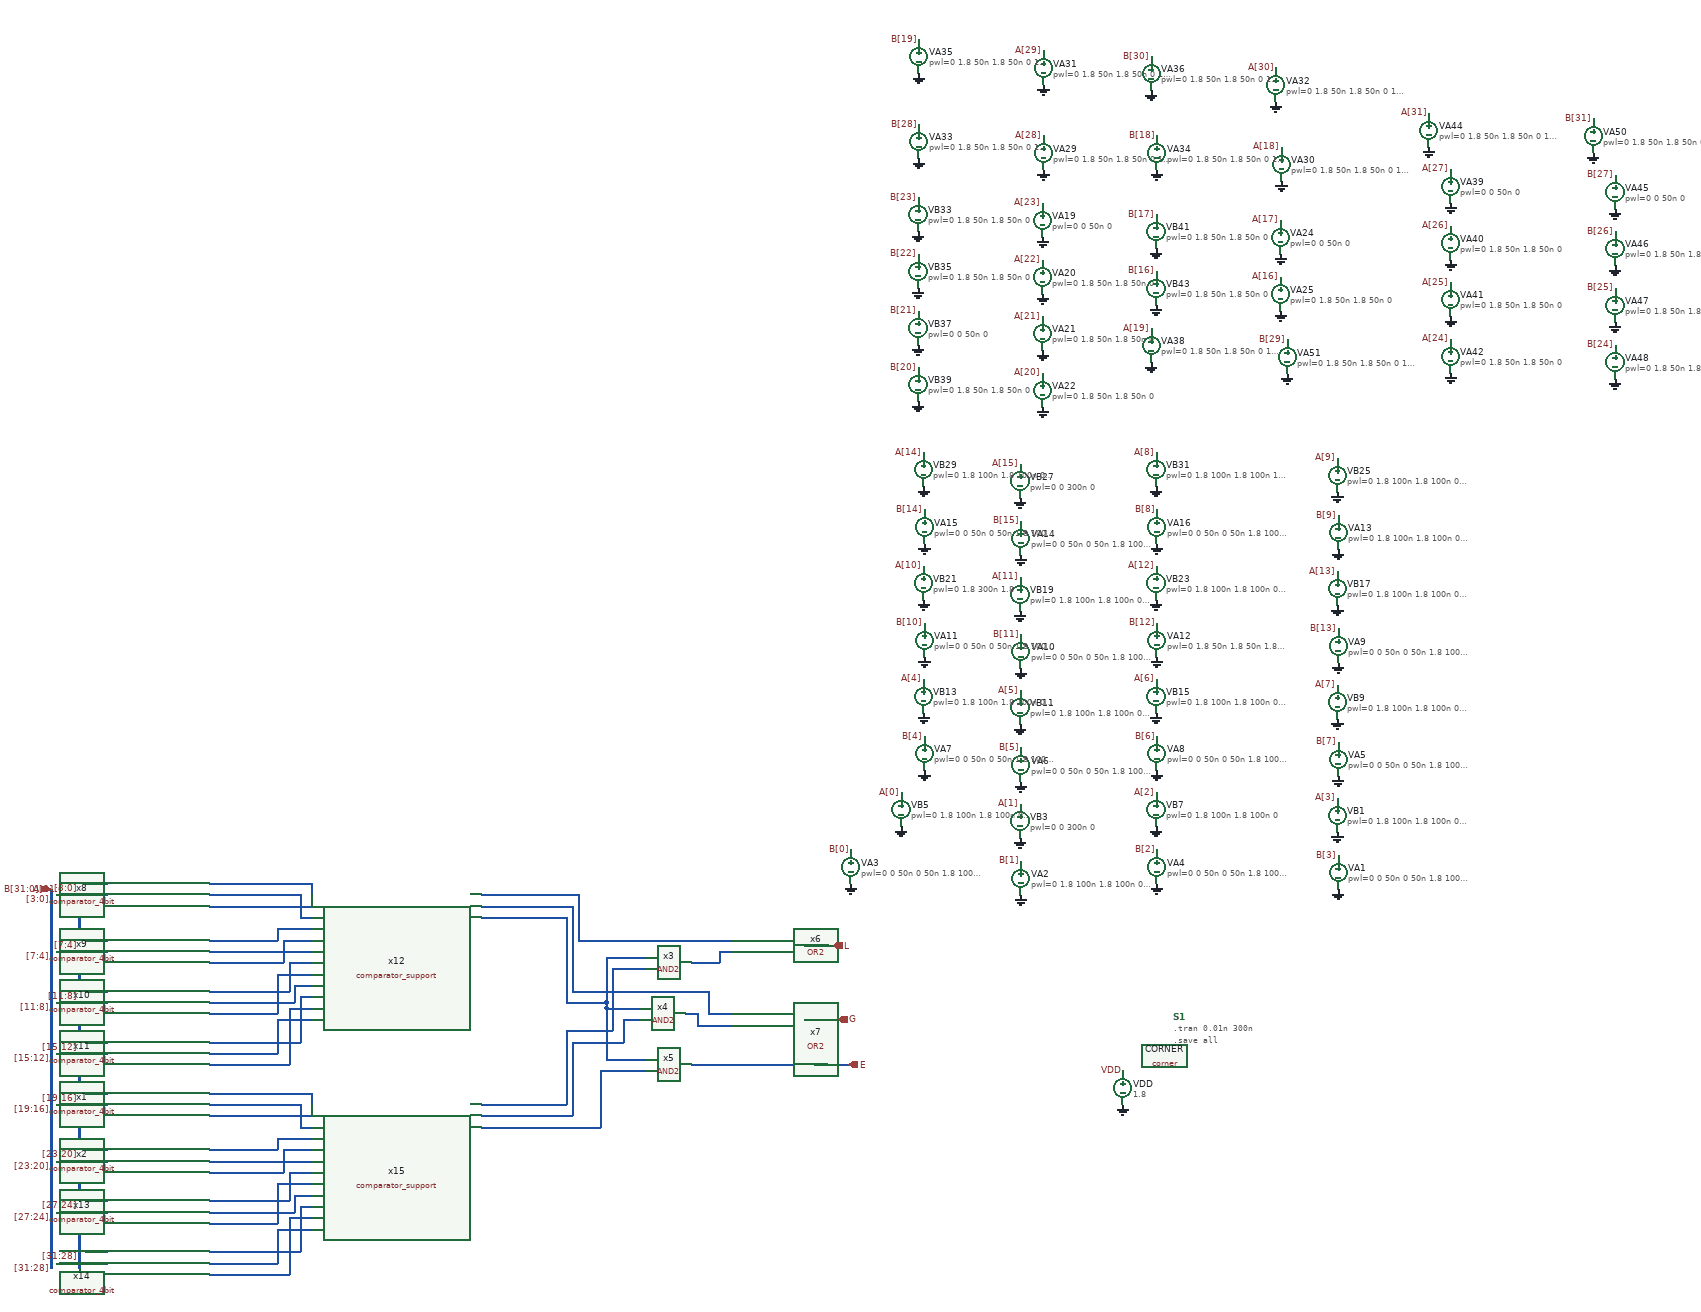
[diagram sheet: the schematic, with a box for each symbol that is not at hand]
v {xschem version=3.4.5 file_version=1.2
}
G {}
K {}
V {}
S {}
E {}
B 2 1100 -540 1900 -140 {flags=graph
y1=0
y2=2
ypos1=-0.3
ypos2=1.7
divy=5
subdivy=1
unity=1
x1=3e-08
x2=1.3e-07
divx=5
subdivx=1
xlabmag=1.0
ylabmag=1.0


dataset=-1
unitx=1
logx=0
logy=0
digital=1
color="12 12 10 10 10"
node="A;a[31],a[30],a[29],a[28],a[27],a[26],a[25],a[24],a[23],a[22],a[21],a[20],a[19],a[18],a[17],a[16],a[15],a[14],a[13],a[12],a[11],a[10],a[9],a[8],a[7],a[6],a[5],a[4],a[3],a[2],a[1],a[0]
B;b[31],b[30],b[29],b[28],b[27],b[26],b[25],b[24],b[23],b[22],b[21],b[20],b[19],b[18],b[17],b[16],b[15],b[14],b[13],b[12],b[11],b[10],b[9],b[8],b[7],b[6],b[5],b[4],b[3],b[2],b[1],b[0]
g
e
l"}
N 550 -960 820 -960 {
lab=#net1}
N 550 -850 570 -850 {
lab=#net2}
N 570 -850 600 -850 {
lab=#net2}
N 600 -930 600 -850 {
lab=#net2}
N 600 -930 670 -930 {
lab=#net2}
N 550 -800 610 -800 {
lab=#net3}
N 610 -910 610 -800 {
lab=#net3}
N 610 -910 670 -910 {
lab=#net3}
N 750 -920 800 -920 {
lab=#net4}
N 800 -940 800 -920 {
lab=#net4}
N 800 -940 820 -940 {
lab=#net4}
N 550 -870 780 -870 {
lab=#net5}
N 780 -870 780 -830 {
lab=#net5}
N 780 -830 820 -830 {
lab=#net5}
N 600 -850 600 -840 {
lab=#net2}
N 600 -840 660 -840 {
lab=#net2}
N 550 -780 630 -780 {
lab=#net6}
N 630 -820 630 -780 {
lab=#net6}
N 630 -820 660 -820 {
lab=#net6}
N 740 -830 760 -830 {
lab=#net7}
N 760 -830 760 -810 {
lab=#net7}
N 760 -810 820 -810 {
lab=#net7}
N 600 -840 600 -750 {
lab=#net2}
N 600 -750 670 -750 {
lab=#net2}
N 590 -730 670 -730 {
lab=#net8}
N 750 -740 990 -740 {
lab=E}
N 949 -820 1009 -820 {
lab=G}
N 968 -740 1028 -740 {
lab=E}
N 991 -950 1001 -950 {
lab=L}
N 949 -950 992 -950 {
lab=L}
N -100 -1020 0 -1020 {
lab=#net9}
N -100 -920 0 -920 {
lab=#net10}
N -100 -830 0 -830 {
lab=#net11}
N -100 -740 0 -740 {
lab=#net12}
N -100 -1060 -20 -1060 {
lab=#net13}
N -100 -960 -60 -960 {
lab=#net14}
N -100 -870 -20 -870 {
lab=#net15}
N -100 -780 -20 -780 {
lab=#net16}
N -100 -760 -40 -760 {
lab=#net17}
N -100 -1040 -40 -1040 {
lab=#net18}
N -100 -940 -40 -940 {
lab=#net19}
N -100 -850 -40 -850 {
lab=#net20}
N 80 -1060 80 -1040 {
lab=#net13}
N -20 -1060 80 -1060 {
lab=#net13}
N 0 -1020 80 -1020 {
lab=#net9}
N -40 -1040 60 -1040 {
lab=#net18}
N 60 -1040 60 -1000 {
lab=#net18}
N 60 -1000 80 -1000 {
lab=#net18}
N -60 -960 20 -960 {
lab=#net14}
N 20 -980 20 -960 {
lab=#net14}
N 20 -980 80 -980 {
lab=#net14}
N -40 -940 80 -940 {
lab=#net19}
N 70 -960 80 -960 {
lab=#net10}
N -20 -870 30 -870 {
lab=#net15}
N 0 -920 30 -920 {
lab=#net10}
N 30 -960 30 -920 {
lab=#net10}
N 30 -960 70 -960 {
lab=#net10}
N 30 -870 40 -870 {
lab=#net15}
N 40 -920 40 -870 {
lab=#net15}
N 40 -920 80 -920 {
lab=#net15}
N -40 -850 50 -850 {
lab=#net20}
N 50 -880 50 -850 {
lab=#net20}
N 50 -880 80 -880 {
lab=#net20}
N 0 -830 20 -830 {
lab=#net11}
N 20 -900 20 -830 {
lab=#net11}
N 20 -900 80 -900 {
lab=#net11}
N -20 -780 60 -780 {
lab=#net16}
N 60 -860 60 -780 {
lab=#net16}
N 60 -860 80 -860 {
lab=#net16}
N 40 -840 80 -840 {
lab=#net12}
N 40 -840 40 -740 {
lab=#net12}
N 0 -740 40 -740 {
lab=#net12}
N -40 -760 20 -760 {
lab=#net17}
N 20 -820 20 -760 {
lab=#net17}
N 20 -820 80 -820 {
lab=#net17}
N -100 -650 0 -650 {
lab=#net21}
N -100 -550 0 -550 {
lab=#net22}
N -100 -460 0 -460 {
lab=#net23}
N -100 -370 0 -370 {
lab=#net24}
N -100 -690 -20 -690 {
lab=#net25}
N -100 -590 -60 -590 {
lab=#net26}
N -100 -500 -20 -500 {
lab=#net27}
N -100 -410 -20 -410 {
lab=#net28}
N -100 -390 -40 -390 {
lab=#net29}
N -100 -670 -40 -670 {
lab=#net30}
N -100 -570 -40 -570 {
lab=#net31}
N -100 -480 -40 -480 {
lab=#net32}
N 80 -690 80 -670 {
lab=#net25}
N -20 -690 80 -690 {
lab=#net25}
N 0 -650 80 -650 {
lab=#net21}
N -40 -670 60 -670 {
lab=#net30}
N 60 -670 60 -630 {
lab=#net30}
N 60 -630 80 -630 {
lab=#net30}
N -60 -590 20 -590 {
lab=#net26}
N 20 -610 20 -590 {
lab=#net26}
N 20 -610 80 -610 {
lab=#net26}
N -40 -570 80 -570 {
lab=#net31}
N 70 -590 80 -590 {
lab=#net22}
N -20 -500 30 -500 {
lab=#net27}
N 0 -550 30 -550 {
lab=#net22}
N 30 -590 30 -550 {
lab=#net22}
N 30 -590 70 -590 {
lab=#net22}
N 30 -500 40 -500 {
lab=#net27}
N 40 -550 40 -500 {
lab=#net27}
N 40 -550 80 -550 {
lab=#net27}
N -40 -480 50 -480 {
lab=#net32}
N 50 -510 50 -480 {
lab=#net32}
N 50 -510 80 -510 {
lab=#net32}
N 0 -460 20 -460 {
lab=#net23}
N 20 -530 20 -460 {
lab=#net23}
N 20 -530 80 -530 {
lab=#net23}
N -20 -410 60 -410 {
lab=#net28}
N 60 -490 60 -410 {
lab=#net28}
N 60 -490 80 -490 {
lab=#net28}
N 40 -470 80 -470 {
lab=#net24}
N 40 -470 40 -370 {
lab=#net24}
N 0 -370 40 -370 {
lab=#net24}
N -40 -390 20 -390 {
lab=#net29}
N 20 -450 20 -390 {
lab=#net29}
N 20 -450 80 -450 {
lab=#net29}
N 380 -1040 550 -1040 {
lab=#net1}
N 550 -1040 550 -960 {
lab=#net1}
N 380 -1000 530 -1000 {
lab=#net2}
N 530 -1000 530 -850 {
lab=#net2}
N 530 -850 550 -850 {
lab=#net2}
N 380 -670 530 -670 {
lab=#net3}
N 530 -800 530 -670 {
lab=#net3}
N 530 -800 550 -800 {
lab=#net3}
N 380 -1020 540 -1020 {
lab=#net5}
N 540 -1020 540 -870 {
lab=#net5}
N 540 -870 550 -870 {
lab=#net5}
N 380 -650 540 -650 {
lab=#net6}
N 540 -780 540 -650 {
lab=#net6}
N 540 -780 550 -780 {
lab=#net6}
N 380 -630 590 -630 {
lab=#net8}
N 590 -730 590 -630 {
lab=#net8}
N -330 -1050 -330 -430 {bus=true lab=A[31:0]}
N -380 -1050 -380 -430 {bus=true lab=B[31:0]}
N -370 -760 -280 -760 {
lab=B[15:12]}
N -320 -780 -280 -780 {
lab=A[15:12]}
N -370 -850 -280 -850 {
lab=B[11:8]}
N -320 -870 -280 -870 {
lab=A[11:8]}
N -370 -940 -280 -940 {
lab=B[7:4]}
N -320 -960 -280 -960 {
lab=A[7:4]}
N -370 -1040 -280 -1040 {
lab=B[3:0]}
N -320 -1060 -280 -1060 {
lab=A[3:0]}
N -380 -430 -380 -380 {
bus=true lab=B[31:0]}
N -330 -430 -330 -380 {bus=true lab=A[31:0]}
N -370 -390 -280 -390 {
lab=B[31:28]}
N -320 -410 -280 -410 {
lab=A[31:28]}
N -370 -480 -280 -480 {
lab=B[27:24]}
N -320 -500 -280 -500 {
lab=A[27:24]}
N -370 -570 -280 -570 {
lab=B[23:20]}
N -320 -590 -280 -590 {
lab=A[23:20]}
N -370 -670 -280 -670 {
lab=B[19:16]}
N -320 -690 -280 -690 {
lab=A[19:16]}
C {devices/ipin.sym} -330 -1050 1 0 {name=p16 sig_type=std_logic lab=A[31:0]}
C {devices/ipin.sym} -380 -1050 1 0 {name=p17 sig_type=std_logic lab=B[31:0]}
C {AND2.sym} 710 -920 0 0 {name=x3}
C {AND2.sym} 700 -830 0 0 {name=x4}
C {AND2.sym} 710 -740 0 0 {name=x5}
C {OR2.sym} 870 -950 0 0 {name=x6}
C {OR2.sym} 870 -820 0 0 {name=x7}
C {devices/opin.sym} 1001 -950 0 0 {name=p8 sig_type=std_logic lab=L}
C {devices/opin.sym} 1009 -820 0 0 {name=p1 sig_type=std_logic lab=G}
C {devices/opin.sym} 1028 -740 0 0 {name=p2 sig_type=std_logic lab=E}
C {devices/vsource.sym} 1511.46728515625 -698.88671875 0 0 {name=VDD value=1.8 savecurrent=false}
C {devices/lab_pin.sym} 1511.46728515625 -728.88671875 0 0 {name=VDD1 sig_type=std_logic lab=VDD}
C {devices/gnd.sym} 1511.46728515625 -668.88671875 0 0 {name=VDD2 lab=GND}
C {devices/vsource.sym} 1891.46728515625 -1078.88671875 0 0 {name=VA1 value="pwl=0 0 50n 0 50n 1.8 100n 1.8 100n 0 300n 0" savecurrent=false}
C {devices/lab_pin.sym} 1891.46728515625 -1108.88671875 0 0 {name=p3 sig_type=std_logic lab=B[3]}
C {devices/gnd.sym} 1891.46728515625 -1048.88671875 0 0 {name=l9 lab=GND}
C {devices/vsource.sym} 1890 -1180 0 0 {name=VB1 value="pwl=0 1.8 100n 1.8 100n 0 300n 0" savecurrent=false}
C {devices/lab_pin.sym} 1890 -1210 0 0 {name=VB2 sig_type=std_logic lab=A[3]}
C {devices/gnd.sym} 1890 -1150 0 0 {name=l10 lab=GND}
C {devices/code_shown.sym} 1600 -825 0 0 {name=S1 only_toplevel=false value=".tran 0.01n 300n
.save all"}
C {sky130_fd_pr/corner.sym} 1585 -755 0 0 {name=CORNER only_toplevel=true corner=tt}
C {devices/vsource.sym} 1331.46728515625 -1068.88671875 0 0 {name=VA2 value="pwl=0 1.8 100n 1.8 100n 0 300n 0" savecurrent=false}
C {devices/lab_pin.sym} 1331.46728515625 -1098.88671875 0 0 {name=p6 sig_type=std_logic lab=B[1]}
C {devices/gnd.sym} 1331.46728515625 -1038.88671875 0 0 {name=l11 lab=GND}
C {devices/vsource.sym} 1330 -1170 0 0 {name=VB3 value="pwl=0 0 300n 0" savecurrent=false}
C {devices/lab_pin.sym} 1330 -1200 0 0 {name=VB4 sig_type=std_logic lab=A[1]}
C {devices/gnd.sym} 1330 -1140 0 0 {name=l12 lab=GND}
C {devices/vsource.sym} 1031.46728515625 -1088.88671875 0 0 {name=VA3 value="pwl=0 0 50n 0 50n 1.8 100n 1.8 100n 0 300n 0" savecurrent=false}
C {devices/lab_pin.sym} 1031.46728515625 -1118.88671875 0 0 {name=p7 sig_type=std_logic lab=B[0]}
C {devices/gnd.sym} 1031.46728515625 -1058.88671875 0 0 {name=l13 lab=GND}
C {devices/vsource.sym} 1120 -1190 0 0 {name=VB5 value="pwl=0 1.8 100n 1.8 100n 0 300n 0" savecurrent=false}
C {devices/lab_pin.sym} 1120 -1220 0 0 {name=VB6 sig_type=std_logic lab=A[0]}
C {devices/gnd.sym} 1120 -1160 0 0 {name=l14 lab=GND}
C {devices/vsource.sym} 1571.46728515625 -1088.88671875 0 0 {name=VA4 value="pwl=0 0 50n 0 50n 1.8 100n 1.8 100n 0 300n 0" savecurrent=false}
C {devices/lab_pin.sym} 1571.46728515625 -1118.88671875 0 0 {name=p9 sig_type=std_logic lab=B[2]}
C {devices/gnd.sym} 1571.46728515625 -1058.88671875 0 0 {name=l15 lab=GND}
C {devices/vsource.sym} 1570 -1190 0 0 {name=VB7 value="pwl=0 1.8 100n 1.8 100n 0" savecurrent=false}
C {devices/lab_pin.sym} 1570 -1220 0 0 {name=VB8 sig_type=std_logic lab=A[2]}
C {devices/gnd.sym} 1570 -1160 0 0 {name=l16 lab=GND}
C {devices/vsource.sym} 1891.46728515625 -1278.88671875 0 0 {name=VA5 value="pwl=0 0 50n 0 50n 1.8 100n 1.8 100n 0 300n 0" savecurrent=false}
C {devices/lab_pin.sym} 1891.46728515625 -1308.88671875 0 0 {name=p4 sig_type=std_logic lab=B[7]}
C {devices/gnd.sym} 1891.46728515625 -1248.88671875 0 0 {name=l17 lab=GND}
C {devices/vsource.sym} 1890 -1380 0 0 {name=VB9 value="pwl=0 1.8 100n 1.8 100n 0 300n 0" savecurrent=false}
C {devices/lab_pin.sym} 1890 -1410 0 0 {name=VB10 sig_type=std_logic lab=A[7]}
C {devices/gnd.sym} 1890 -1350 0 0 {name=l18 lab=GND}
C {devices/vsource.sym} 1331.46728515625 -1268.88671875 0 0 {name=VA6 value="pwl=0 0 50n 0 50n 1.8 100n 1.8 100n 0 300n 0" savecurrent=false}
C {devices/lab_pin.sym} 1331.46728515625 -1298.88671875 0 0 {name=p5 sig_type=std_logic lab=B[5]}
C {devices/gnd.sym} 1331.46728515625 -1238.88671875 0 0 {name=l19 lab=GND}
C {devices/vsource.sym} 1330 -1370 0 0 {name=VB11 value="pwl=0 1.8 100n 1.8 100n 0 300n 0" savecurrent=false}
C {devices/lab_pin.sym} 1330 -1400 0 0 {name=VB12 sig_type=std_logic lab=A[5]}
C {devices/gnd.sym} 1330 -1340 0 0 {name=l20 lab=GND}
C {devices/vsource.sym} 1161.46728515625 -1288.88671875 0 0 {name=VA7 value="pwl=0 0 50n 0 50n 1.8 100n 1.8 100n 0 300n 0" savecurrent=false}
C {devices/lab_pin.sym} 1161.46728515625 -1318.88671875 0 0 {name=p10 sig_type=std_logic lab=B[4]}
C {devices/gnd.sym} 1161.46728515625 -1258.88671875 0 0 {name=l21 lab=GND}
C {devices/vsource.sym} 1160 -1390 0 0 {name=VB13 value="pwl=0 1.8 100n 1.8 100n 0 300n 0" savecurrent=false}
C {devices/lab_pin.sym} 1160 -1420 0 0 {name=VB14 sig_type=std_logic lab=A[4]}
C {devices/gnd.sym} 1160 -1360 0 0 {name=l22 lab=GND}
C {devices/vsource.sym} 1571.46728515625 -1288.88671875 0 0 {name=VA8 value="pwl=0 0 50n 0 50n 1.8 100n 1.8 100n 0 300n 0" savecurrent=false}
C {devices/lab_pin.sym} 1571.46728515625 -1318.88671875 0 0 {name=p11 sig_type=std_logic lab=B[6]}
C {devices/gnd.sym} 1571.46728515625 -1258.88671875 0 0 {name=l23 lab=GND}
C {devices/vsource.sym} 1570 -1390 0 0 {name=VB15 value="pwl=0 1.8 100n 1.8 100n 0 300n 0" savecurrent=false}
C {devices/lab_pin.sym} 1570 -1420 0 0 {name=VB16 sig_type=std_logic lab=A[6]}
C {devices/gnd.sym} 1570 -1360 0 0 {name=l24 lab=GND}
C {devices/vsource.sym} 1891.46728515625 -1478.88671875 0 0 {name=VA9 value="pwl=0 0 50n 0 50n 1.8 100n 1.8 100n 0 300n 0" savecurrent=false}
C {devices/lab_pin.sym} 1891.46728515625 -1508.88671875 0 0 {name=p12 sig_type=std_logic lab=B[13]}
C {devices/gnd.sym} 1891.46728515625 -1448.88671875 0 0 {name=l25 lab=GND}
C {devices/vsource.sym} 1890 -1580 0 0 {name=VB17 value="pwl=0 1.8 100n 1.8 100n 0 300n 0" savecurrent=false}
C {devices/lab_pin.sym} 1890 -1610 0 0 {name=VB18 sig_type=std_logic lab=A[13]}
C {devices/gnd.sym} 1890 -1550 0 0 {name=l26 lab=GND}
C {devices/vsource.sym} 1331.46728515625 -1468.88671875 0 0 {name=VA10 value="pwl=0 0 50n 0 50n 1.8 100n 1.8 100n 0 300n 0" savecurrent=false}
C {devices/lab_pin.sym} 1331.46728515625 -1498.88671875 0 0 {name=p13 sig_type=std_logic lab=B[11]}
C {devices/gnd.sym} 1331.46728515625 -1438.88671875 0 0 {name=l27 lab=GND}
C {devices/vsource.sym} 1330 -1570 0 0 {name=VB19 value="pwl=0 1.8 100n 1.8 100n 0 300n 0" savecurrent=false}
C {devices/lab_pin.sym} 1330 -1600 0 0 {name=VB20 sig_type=std_logic lab=A[11]}
C {devices/gnd.sym} 1330 -1540 0 0 {name=l28 lab=GND}
C {devices/vsource.sym} 1161.46728515625 -1488.88671875 0 0 {name=VA11 value="pwl=0 0 50n 0 50n 1.8 100n 1.8 100n 0 300n 0" savecurrent=false}
C {devices/lab_pin.sym} 1161.46728515625 -1518.88671875 0 0 {name=p14 sig_type=std_logic lab=B[10]}
C {devices/gnd.sym} 1161.46728515625 -1458.88671875 0 0 {name=l29 lab=GND}
C {devices/vsource.sym} 1160 -1590 0 0 {name=VB21 value="pwl=0 1.8 300n 1.8" savecurrent=false}
C {devices/lab_pin.sym} 1160 -1620 0 0 {name=VB22 sig_type=std_logic lab=A[10]}
C {devices/gnd.sym} 1160 -1560 0 0 {name=l30 lab=GND}
C {devices/vsource.sym} 1571.46728515625 -1488.88671875 0 0 {name=VA12 value="pwl=0 1.8 50n 1.8 50n 1.8 100n 1.8 100n 0 300n 0" savecurrent=false}
C {devices/lab_pin.sym} 1571.46728515625 -1518.88671875 0 0 {name=p15 sig_type=std_logic lab=B[12]}
C {devices/gnd.sym} 1571.46728515625 -1458.88671875 0 0 {name=l31 lab=GND}
C {devices/vsource.sym} 1570 -1590 0 0 {name=VB23 value="pwl=0 1.8 100n 1.8 100n 0 300n 0" savecurrent=false}
C {devices/lab_pin.sym} 1570 -1620 0 0 {name=VB24 sig_type=std_logic lab=A[12]}
C {devices/gnd.sym} 1570 -1560 0 0 {name=l32 lab=GND}
C {devices/vsource.sym} 1891.46728515625 -1678.88671875 0 0 {name=VA13 value="pwl=0 1.8 100n 1.8 100n 0 300n 0" savecurrent=false}
C {devices/lab_pin.sym} 1891.46728515625 -1708.88671875 0 0 {name=p18 sig_type=std_logic lab=B[9]}
C {devices/gnd.sym} 1891.46728515625 -1648.88671875 0 0 {name=l33 lab=GND}
C {devices/vsource.sym} 1890 -1780 0 0 {name=VB25 value="pwl=0 1.8 100n 1.8 100n 0 300n 0" savecurrent=false}
C {devices/lab_pin.sym} 1890 -1810 0 0 {name=VB26 sig_type=std_logic lab=A[9]}
C {devices/gnd.sym} 1890 -1750 0 0 {name=l34 lab=GND}
C {devices/vsource.sym} 1331.46728515625 -1668.88671875 0 0 {name=VA14 value="pwl=0 0 50n 0 50n 1.8 100n 1.8 100n 0 300n 0" savecurrent=false}
C {devices/lab_pin.sym} 1331.46728515625 -1698.88671875 0 0 {name=p19 sig_type=std_logic lab=B[15]}
C {devices/gnd.sym} 1331.46728515625 -1638.88671875 0 0 {name=l35 lab=GND}
C {devices/vsource.sym} 1330 -1770 0 0 {name=VB27 value="pwl=0 0 300n 0 " savecurrent=false}
C {devices/lab_pin.sym} 1330 -1800 0 0 {name=VB28 sig_type=std_logic lab=A[15]}
C {devices/gnd.sym} 1330 -1740 0 0 {name=l36 lab=GND}
C {devices/vsource.sym} 1161.46728515625 -1688.88671875 0 0 {name=VA15 value="pwl=0 0 50n 0 50n 1.8 100n 1.8 100n 0 300n 0" savecurrent=false}
C {devices/lab_pin.sym} 1161.46728515625 -1718.88671875 0 0 {name=p20 sig_type=std_logic lab=B[14]}
C {devices/gnd.sym} 1161.46728515625 -1658.88671875 0 0 {name=l37 lab=GND}
C {devices/vsource.sym} 1160 -1790 0 0 {name=VB29 value="pwl=0 1.8 100n 1.8 100n 0 300n 0" savecurrent=false}
C {devices/lab_pin.sym} 1160 -1820 0 0 {name=VB30 sig_type=std_logic lab=A[14]}
C {devices/gnd.sym} 1160 -1760 0 0 {name=l38 lab=GND}
C {devices/vsource.sym} 1571.46728515625 -1688.88671875 0 0 {name=VA16 value="pwl=0 0 50n 0 50n 1.8 100n 1.8 100n 0 300n 0" savecurrent=false}
C {devices/lab_pin.sym} 1571.46728515625 -1718.88671875 0 0 {name=p21 sig_type=std_logic lab=B[8]}
C {devices/gnd.sym} 1571.46728515625 -1658.88671875 0 0 {name=l39 lab=GND}
C {devices/vsource.sym} 1570 -1790 0 0 {name=VB31 value="pwl=0 1.8 100n 1.8 100n 1.8 300n 1.8" savecurrent=false}
C {devices/lab_pin.sym} 1570 -1820 0 0 {name=VB32 sig_type=std_logic lab=A[8]}
C {devices/gnd.sym} 1570 -1760 0 0 {name=l40 lab=GND}
C {devices/vsource.sym} 1370 -2230 0 0 {name=VA19 value="pwl=0 0 50n 0" savecurrent=false}
C {devices/lab_pin.sym} 1370 -2260 0 0 {name=p22 sig_type=std_logic lab=A[23]}
C {devices/vsource.sym} 1370 -2130 0 0 {name=VA20 value="pwl=0 1.8 50n 1.8 50n 0" savecurrent=false}
C {devices/lab_pin.sym} 1370 -2160 0 0 {name=p23 sig_type=std_logic lab=A[22]}
C {devices/vsource.sym} 1370 -2030 0 0 {name=VA21 value="pwl=0 1.8 50n 1.8 50n 0" savecurrent=false}
C {devices/lab_pin.sym} 1370 -2060 0 0 {name=p24 sig_type=std_logic lab=A[21]}
C {devices/vsource.sym} 1370 -1930 0 0 {name=VA22 value="pwl=0 1.8 50n 1.8 50n 0" savecurrent=false}
C {devices/lab_pin.sym} 1370 -1960 0 0 {name=VA23 sig_type=std_logic lab=A[20]}
C {devices/vsource.sym} 1150 -2240 0 0 {name=VB33 value="pwl=0 1.8 50n 1.8 50n 0" savecurrent=false}
C {devices/lab_pin.sym} 1150 -2270 0 0 {name=VB34 sig_type=std_logic lab=B[23]}
C {devices/vsource.sym} 1150 -2140 0 0 {name=VB35 value="pwl=0 1.8 50n 1.8 50n 0" savecurrent=false}
C {devices/lab_pin.sym} 1150 -2170 0 0 {name=VB36 sig_type=std_logic lab=B[22]}
C {devices/vsource.sym} 1150 -2040 0 0 {name=VB37 value="pwl=0 0 50n 0 " savecurrent=false}
C {devices/lab_pin.sym} 1150 -2070 0 0 {name=VB38 sig_type=std_logic lab=B[21]}
C {devices/vsource.sym} 1150 -1940 0 0 {name=VB39 value="pwl=0 1.8 50n 1.8 50n 0" savecurrent=false}
C {devices/lab_pin.sym} 1150 -1970 0 0 {name=VB40 sig_type=std_logic lab=B[20]}
C {devices/gnd.sym} 1370 -1900 0 0 {name=l91 lab=GND}
C {devices/gnd.sym} 1150 -1910 0 0 {name=l92 lab=GND}
C {devices/gnd.sym} 1370 -2000 0 0 {name=l93 lab=GND}
C {devices/gnd.sym} 1150 -2010 0 0 {name=l94 lab=GND}
C {devices/gnd.sym} 1370 -2100 0 0 {name=l95 lab=GND}
C {devices/gnd.sym} 1150 -2110 0 0 {name=l96 lab=GND}
C {devices/gnd.sym} 1150 -2210 0 0 {name=l97 lab=GND}
C {devices/gnd.sym} 1370 -2200 0 0 {name=l98 lab=GND}
C {devices/vsource.sym} 1790 -2200 0 0 {name=VA24 value="pwl=0 0 50n 0" savecurrent=false}
C {devices/lab_pin.sym} 1790 -2230 0 0 {name=p25 sig_type=std_logic lab=A[17]}
C {devices/vsource.sym} 1790 -2100 0 0 {name=VA25 value="pwl=0 1.8 50n 1.8 50n 0" savecurrent=false}
C {devices/lab_pin.sym} 1790 -2130 0 0 {name=p26 sig_type=std_logic lab=A[16]}
C {devices/vsource.sym} 1570 -2210 0 0 {name=VB41 value="pwl=0 1.8 50n 1.8 50n 0" savecurrent=false}
C {devices/lab_pin.sym} 1570 -2240 0 0 {name=VB42 sig_type=std_logic lab=B[17]}
C {devices/vsource.sym} 1570 -2110 0 0 {name=VB43 value="pwl=0 1.8 50n 1.8 50n 0" savecurrent=false}
C {devices/lab_pin.sym} 1570 -2140 0 0 {name=VB44 sig_type=std_logic lab=B[16]}
C {devices/gnd.sym} 1790 -2070 0 0 {name=l103 lab=GND}
C {devices/gnd.sym} 1570 -2080 0 0 {name=l104 lab=GND}
C {devices/gnd.sym} 1570 -2180 0 0 {name=l105 lab=GND}
C {devices/gnd.sym} 1790 -2170 0 0 {name=l106 lab=GND}
C {devices/vsource.sym} 1371.46728515625 -2348.88671875 0 0 {name=VA29 value="pwl=0 1.8 50n 1.8 50n 0 100n 0" savecurrent=false}
C {devices/lab_pin.sym} 1371.46728515625 -2378.88671875 0 0 {name=p28 sig_type=std_logic lab=A[28]}
C {devices/gnd.sym} 1371.46728515625 -2318.88671875 0 0 {name=l107 lab=GND}
C {devices/vsource.sym} 1791.46728515625 -2328.88671875 0 0 {name=VA30 value="pwl=0 1.8 50n 1.8 50n 0 100n 0" savecurrent=false}
C {devices/lab_pin.sym} 1791.46728515625 -2358.88671875 0 0 {name=p29 sig_type=std_logic lab=A[18]}
C {devices/gnd.sym} 1791.46728515625 -2298.88671875 0 0 {name=l108 lab=GND}
C {devices/vsource.sym} 1371.46728515625 -2498.88671875 0 0 {name=VA31 value="pwl=0 1.8 50n 1.8 50n 0 100n 0" savecurrent=false}
C {devices/lab_pin.sym} 1371.46728515625 -2528.88671875 0 0 {name=p30 sig_type=std_logic lab=A[29]}
C {devices/gnd.sym} 1371.46728515625 -2468.88671875 0 0 {name=l109 lab=GND}
C {devices/vsource.sym} 1781.46728515625 -2468.88671875 0 0 {name=VA32 value="pwl=0 1.8 50n 1.8 50n 0 100n 0" savecurrent=false}
C {devices/lab_pin.sym} 1781.46728515625 -2498.88671875 0 0 {name=p31 sig_type=std_logic lab=A[30]}
C {devices/gnd.sym} 1781.46728515625 -2438.88671875 0 0 {name=l110 lab=GND}
C {devices/vsource.sym} 1151.46728515625 -2368.88671875 0 0 {name=VA33 value="pwl=0 1.8 50n 1.8 50n 0 100n 0" savecurrent=false}
C {devices/lab_pin.sym} 1151.46728515625 -2398.88671875 0 0 {name=p32 sig_type=std_logic lab=B[28]}
C {devices/gnd.sym} 1151.46728515625 -2338.88671875 0 0 {name=l111 lab=GND}
C {devices/vsource.sym} 1571.46728515625 -2348.88671875 0 0 {name=VA34 value="pwl=0 1.8 50n 1.8 50n 0 100n 0" savecurrent=false}
C {devices/lab_pin.sym} 1571.46728515625 -2378.88671875 0 0 {name=p33 sig_type=std_logic lab=B[18]}
C {devices/gnd.sym} 1571.46728515625 -2318.88671875 0 0 {name=l112 lab=GND}
C {devices/vsource.sym} 1151.46728515625 -2518.88671875 0 0 {name=VA35 value="pwl=0 1.8 50n 1.8 50n 0 100n 0" savecurrent=false}
C {devices/lab_pin.sym} 1151.46728515625 -2548.88671875 0 0 {name=p34 sig_type=std_logic lab=B[19]}
C {devices/gnd.sym} 1151.46728515625 -2488.88671875 0 0 {name=l113 lab=GND}
C {devices/vsource.sym} 1561.46728515625 -2488.88671875 0 0 {name=VA36 value="pwl=0 1.8 50n 1.8 50n 0 100n 0" savecurrent=false}
C {devices/lab_pin.sym} 1561.46728515625 -2518.88671875 0 0 {name=p35 sig_type=std_logic lab=B[30]}
C {devices/gnd.sym} 1561.46728515625 -2458.88671875 0 0 {name=l114 lab=GND}
C {devices/vsource.sym} 1561.46728515625 -2008.88671875 0 0 {name=VA38 value="pwl=0 1.8 50n 1.8 50n 0 100n 0" savecurrent=false}
C {devices/lab_pin.sym} 1561.46728515625 -2038.88671875 0 0 {name=p36 sig_type=std_logic lab=A[19]}
C {devices/gnd.sym} 1561.46728515625 -1978.88671875 0 0 {name=l117 lab=GND}
C {devices/vsource.sym} 2090 -2290 0 0 {name=VA39 value="pwl=0 0 50n 0" savecurrent=false}
C {devices/lab_pin.sym} 2090 -2320 0 0 {name=p37 sig_type=std_logic lab=A[27]}
C {devices/vsource.sym} 2090 -2190 0 0 {name=VA40 value="pwl=0 1.8 50n 1.8 50n 0" savecurrent=false}
C {devices/lab_pin.sym} 2090 -2220 0 0 {name=p38 sig_type=std_logic lab=A[26]}
C {devices/vsource.sym} 2090 -2090 0 0 {name=VA41 value="pwl=0 1.8 50n 1.8 50n 0" savecurrent=false}
C {devices/lab_pin.sym} 2090 -2120 0 0 {name=p39 sig_type=std_logic lab=A[25]}
C {devices/vsource.sym} 2090 -1990 0 0 {name=VA42 value="pwl=0 1.8 50n 1.8 50n 0" savecurrent=false}
C {devices/lab_pin.sym} 2090 -2020 0 0 {name=VA43 sig_type=std_logic lab=A[24]}
C {devices/gnd.sym} 2090 -1960 0 0 {name=l118 lab=GND}
C {devices/gnd.sym} 2090 -2060 0 0 {name=l119 lab=GND}
C {devices/gnd.sym} 2090 -2160 0 0 {name=l120 lab=GND}
C {devices/gnd.sym} 2090 -2260 0 0 {name=l121 lab=GND}
C {devices/vsource.sym} 2051.46728515625 -2388.88671875 0 0 {name=VA44 value="pwl=0 1.8 50n 1.8 50n 0 100n 0" savecurrent=false}
C {devices/lab_pin.sym} 2051.46728515625 -2418.88671875 0 0 {name=p40 sig_type=std_logic lab=A[31]}
C {devices/gnd.sym} 2051.46728515625 -2358.88671875 0 0 {name=l122 lab=GND}
C {devices/vsource.sym} 2380 -2280 0 0 {name=VA45 value="pwl=0 0 50n 0" savecurrent=false}
C {devices/lab_pin.sym} 2380 -2310 0 0 {name=p41 sig_type=std_logic lab=B[27]}
C {devices/vsource.sym} 2380 -2180 0 0 {name=VA46 value="pwl=0 1.8 50n 1.8 50n 0" savecurrent=false}
C {devices/lab_pin.sym} 2380 -2210 0 0 {name=p42 sig_type=std_logic lab=B[26]}
C {devices/vsource.sym} 2380 -2080 0 0 {name=VA47 value="pwl=0 1.8 50n 1.8 50n 0" savecurrent=false}
C {devices/lab_pin.sym} 2380 -2110 0 0 {name=p43 sig_type=std_logic lab=B[25]}
C {devices/vsource.sym} 2380 -1980 0 0 {name=VA48 value="pwl=0 1.8 50n 1.8 50n 0" savecurrent=false}
C {devices/lab_pin.sym} 2380 -2010 0 0 {name=VA49 sig_type=std_logic lab=B[24]}
C {devices/gnd.sym} 2380 -1950 0 0 {name=l123 lab=GND}
C {devices/gnd.sym} 2380 -2050 0 0 {name=l124 lab=GND}
C {devices/gnd.sym} 2380 -2150 0 0 {name=l125 lab=GND}
C {devices/gnd.sym} 2380 -2250 0 0 {name=l126 lab=GND}
C {devices/vsource.sym} 2341.46728515625 -2378.88671875 0 0 {name=VA50 value="pwl=0 1.8 50n 1.8 50n 0 100n 0" savecurrent=false}
C {devices/lab_pin.sym} 2341.46728515625 -2408.88671875 0 0 {name=p44 sig_type=std_logic lab=B[31]}
C {devices/gnd.sym} 2341.46728515625 -2348.88671875 0 0 {name=l127 lab=GND}
C {devices/vsource.sym} 1801.46728515625 -1988.88671875 0 0 {name=VA51 value="pwl=0 1.8 50n 1.8 50n 0 100n 0" savecurrent=false}
C {devices/lab_pin.sym} 1801.46728515625 -2018.88671875 0 0 {name=p45 sig_type=std_logic lab=B[29]}
C {devices/gnd.sym} 1801.46728515625 -1958.88671875 0 0 {name=l128 lab=GND}
C {comparator_4bit.sym} -190 -1040 0 0 {name=x8}
C {comparator_4bit.sym} -190 -940 0 0 {name=x9}
C {comparator_4bit.sym} -190 -850 0 0 {name=x10}
C {comparator_4bit.sym} -190 -760 0 0 {name=x11}
C {comparator_support.sym} 230 -930 0 0 {name=x12}
C {comparator_4bit.sym} -190 -670 0 0 {name=x1}
C {comparator_4bit.sym} -190 -570 0 0 {name=x2}
C {comparator_4bit.sym} -190 -480 0 0 {name=x13}
C {comparator_4bit.sym} -190 -390 0 0 {name=x14}
C {comparator_support.sym} 230 -560 0 0 {name=x15}
C {devices/bus_tap.sym} -330 -1050 0 0 {name=l1 lab=[3:0]}
C {devices/bus_tap.sym} -330 -950 0 0 {name=l2 lab=[7:4]}
C {devices/bus_tap.sym} -330 -770 0 0 {name=l3 lab=[15:12]}
C {devices/bus_tap.sym} -330 -860 0 0 {name=l4 lab=[11:8]}
C {devices/bus_tap.sym} -380 -750 0 0 {name=l5 lab=[15:12]}
C {devices/bus_tap.sym} -380 -840 0 0 {name=l6 lab=[11:8]}
C {devices/bus_tap.sym} -380 -930 0 0 {name=l7 lab=[7:4]}
C {devices/bus_tap.sym} -380 -1030 0 0 {name=l8 lab=[3:0]}
C {devices/bus_tap.sym} -330 -680 0 0 {name=l41 lab=[19:16]}
C {devices/bus_tap.sym} -330 -580 0 0 {name=l42 lab=[23:20]}
C {devices/bus_tap.sym} -330 -490 0 0 {name=l43 lab=[27:24]}
C {devices/bus_tap.sym} -330 -400 0 0 {name=l44 lab=[31:28]}
C {devices/bus_tap.sym} -380 -660 0 0 {name=l45 lab=[19:16]}
C {devices/bus_tap.sym} -380 -560 0 0 {name=l46 lab=[23:20]}
C {devices/bus_tap.sym} -380 -470 0 0 {name=l47 lab=[27:24]}
C {devices/bus_tap.sym} -380 -380 0 0 {name=l48 lab=[31:28]}
